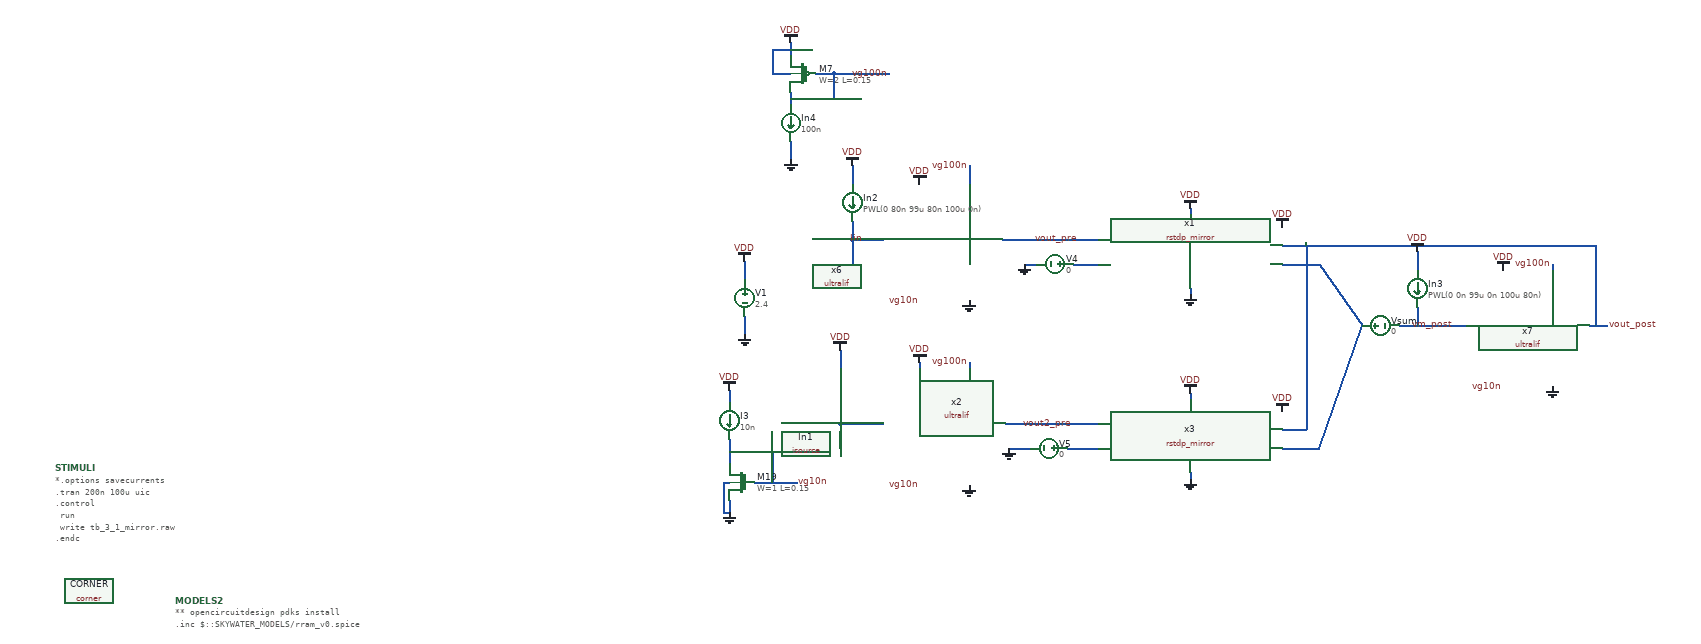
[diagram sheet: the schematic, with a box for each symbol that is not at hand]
v {xschem version=3.4.5 file_version=1.2
}
G {}
K {}
V {}
S {}
E {}
B 2 1390 -105 2190 295 {flags=graph
y1=1.8
y2=5.3
ypos1=0
ypos2=2
divy=5
subdivy=1
unity=1
x1=2e-09
x2=0.0001
divx=5
subdivx=1
xlabmag=1.0
ylabmag=1.0
node="\\"Fil1; 5 n.x1.x1.xr2.n1#ngap -\\"

\\"Fil2; 5 n.x3.x1.xr2.n1#ngap - \\"

\\"Fil2; 5 n.x5.x1.xr2.n1#ngap - \\""
color="6 8 7"
dataset=-1
unitx=1
logx=0
logy=0
}
B 2 1355 535 2155 935 {flags=graph
y1=-1.4047916
y2=0.79520803
ypos1=0
ypos2=2
divy=5
subdivy=1
unity=1
x1=2e-09
x2=0.0001
divx=5
subdivx=1
xlabmag=1.0
ylabmag=1.0


dataset=-1
unitx=1
logx=0
logy=0
color=4
node="\\"Vmem1; x1.x1.BE x1.x1.TE - \\""}
B 2 1620 -610 2420 -210 {flags=graph
y1=-0.0056
y2=2.5
ypos1=0
ypos2=2
divy=5
subdivy=1
unity=1
x1=2e-09
x2=0.0001
divx=5
subdivx=1
xlabmag=1.0
ylabmag=1.0


dataset=-1
unitx=1
logx=0
logy=0
color=8
node=vout_post}
B 2 -1232.5 -695 -432.5 -295 {flags=graph
y1=-0.00026
y2=2.5
ypos1=0
ypos2=2
divy=5
subdivy=1
unity=1
x1=2e-09
x2=0.0001
divx=5
subdivx=1
xlabmag=1.0
ylabmag=1.0


dataset=-1
unitx=1
logx=0
logy=0
color=6
node=vout_pre}
B 2 -200 -740 600 -340 {flags=graph
y1=-2.4011863e-07
y2=1.3746887e-06
ypos1=0
ypos2=2
divy=5
subdivy=1
unity=1
x1=2e-09
x2=0.0001
divx=5
subdivx=1
xlabmag=1.0
ylabmag=1.0


dataset=-1
unitx=1
logx=0
logy=0
color=6
node=i(Vsum)}
B 2 -1225 -177.5 -425 222.5 {flags=graph
y1=-0.0017
y2=2.8
ypos1=0
ypos2=2
divy=5
subdivy=1
unity=1
x1=2e-09
x2=0.0001
divx=5
subdivx=1
xlabmag=1.0
ylabmag=1.0


dataset=-1
unitx=1
logx=0
logy=0
color=8
node=vout2_pre}
B 2 702.5 -630 1502.5 -230 {flags=graph
y1=0.018
y2=1.7
ypos1=0
ypos2=2
divy=5
subdivy=1
unity=1
x1=2e-09
x2=0.0001
divx=5
subdivx=1
xlabmag=1.0
ylabmag=1.0


dataset=-1
unitx=1
logx=0
logy=0




color=4
node=x7.vm}
B 2 402.5 515 1202.5 915 {flags=graph
y1=-0.0011
y2=1.3
ypos1=0
ypos2=2
divy=5
subdivy=1
unity=1
x1=2e-09
x2=0.0001
divx=5
subdivx=1
xlabmag=1.0
ylabmag=1.0


dataset=-1
unitx=1
logx=0
logy=0




color=4
node=x7.vg}
B 2 -557.5 530 242.5 930 {flags=graph
y1=-1.4e-06
y2=3.9e-06
ypos1=0
ypos2=2
divy=5
subdivy=1
unity=1
x1=2e-09
x2=0.0001
divx=5
subdivx=1
xlabmag=1.0
ylabmag=1.0


dataset=-1
unitx=1
logx=0
logy=0




color=4
node=i(v4)}
N -175 125 -175 155 {
lab=GND}
N -175 35 -175 65 {
lab=VDD}
N -200 325 -200 365 {
lab=vg10n}
N -200 245 -200 265 {
lab=VDD}
N -200 425 -200 445 {
lab=GND}
N -210 395 -200 395 {
lab=GND}
N -210 395 -210 445 {
lab=GND}
N -210 445 -200 445 {
lab=GND}
N -160 395 -90 395 {
lab=vg10n}
N -200 345 -130 345 {
lab=vg10n}
N -130 345 -130 395 {
lab=vg10n}
N 550 -50 550 -40 {
lab=VDD}
N 340 0 400 0 {
lab=vout_pre}
N 550 80 550 90 {
lab=GND}
N 0 0 50 0 {
lab=Iin}
N 0 -30 0 0 {
lab=Iin}
N 0 -120 0 -90 {
lab=VDD}
N -20 270 -20 300 {
lab=#net1}
N -20 180 -20 210 {
lab=VDD}
N -20 300 50 300 {
lab=#net1}
N 110 200 110 210 {
lab=VDD}
N 550 250 550 260 {
lab=VDD}
N 550 380 550 390 {
lab=GND}
N 340 300 400 300 {
lab=vout2_pre}
N 1200 140 1230 140 {
lab=vout_post}
N 930 10 1210 10 {
lab=vout_post}
N 1210 10 1210 140 {
lab=vout_post}
N -100 -320 -100 -300 {
lab=VDD}
N -130 -270 -100 -270 {
lab=VDD}
N -130 -310 -130 -270 {
lab=VDD}
N -130 -310 -100 -310 {
lab=VDD}
N -60 -270 -30 -270 {
lab=vg100n}
N -100 -240 -100 -220 {
lab=vg100n}
N -100 -160 -100 -130 {
lab=GND}
N -100 -230 -30 -230 {
lab=vg100n}
N -30 -270 -30 -230 {
lab=vg100n}
N -30 -270 60 -270 {
lab=vg100n}
N 190 -120 190 -90 {
lab=vg100n}
N 190 200 190 210 {
lab=vg100n}
N 1140 40 1140 50 {
lab=vg100n}
N 700 10 820 10 {
lab=vout_post}
N 820 10 930 10 {
lab=vout_post}
N 700 40 760 40 {
lab=#net2}
N 700 340 760 340 {
lab=#net2}
N 360 40 400 40 {
lab=#net3}
N 350 340 400 340 {
lab=#net4}
N 890 140 1000 140 {
lab=vm_post}
N 920 20 920 50 {
lab=VDD}
N 920 110 920 140 {
lab=vm_post}
N 760 340 830 140 {
lab=#net2}
N 760 40 830 140 {
lab=#net2}
N 245 -0 340 0 {
lab=vout_pre}
N -0 -0 0 40 {
lab=Iin}
N -20 300 -20 340 {
lab=#net1}
N 250 300 340 300 {
lab=vout2_pre}
N 255 340 290 340 {
lab=GND}
N 280 40 300 40 {
lab=GND}
N 740 10 740 305 {
lab=vout_post}
N 700 310 740 310 {
lab=vout_post}
N 740 305 740 310 {
lab=vout_post}
C {devices/vsource.sym} -175 95 0 0 {name=V1 value=2.4 savecurrent=false}
C {devices/vdd.sym} -175 35 0 0 {name=l1 lab=VDD}
C {devices/gnd.sym} -175 155 0 0 {name=l2 lab=GND}
C {sky130_fd_pr/corner.sym} -1242.5 572.5 0 0 {name=CORNER only_toplevel=true corner=tt}
C {devices/code_shown.sym} -1297.5 372.5 0 0 {name=STIMULI 
only_toplevel=true
place=end
value="
*.options savecurrents
.tran 200n 100u uic
.control
	run
	write tb_3_1_mirror.raw
.endc
"}
C {devices/code.sym} -1102.5 587.5 0 0 {name=MODELS2
only_toplevel=true
format="tcleval( @value )"
value="
** opencircuitdesign pdks install
.inc $::SKYWATER_MODELS/rram_v0.spice
"
spice_ignore=false}
C {/home/alex/Desktop/EDA/SNN_IPN/Neuron/ultralif/ultralif.sym} 150 0 0 0 {name=x6}
C {/home/alex/Desktop/EDA/SNN_IPN/Neuron/ultralif/ultralif.sym} 1100 140 0 0 {name=x7}
C {sky130_fd_pr/nfet_01v8.sym} -180 395 0 1 {name=M19
L=0.15
W=1
nf=1 
mult=1
ad="'int((nf+1)/2) * W/nf * 0.29'" 
pd="'2*int((nf+1)/2) * (W/nf + 0.29)'"
as="'int((nf+2)/2) * W/nf * 0.29'" 
ps="'2*int((nf+2)/2) * (W/nf + 0.29)'"
nrd="'0.29 / W'" nrs="'0.29 / W'"
sa=0 sb=0 sd=0
model=nfet_01v8
spiceprefix=X
}
C {devices/isource.sym} -200 295 0 0 {name=I3 value=10n}
C {devices/vdd.sym} -200 245 0 0 {name=l30 lab=VDD}
C {devices/gnd.sym} -200 445 0 0 {name=l31 lab=GND}
C {devices/vdd.sym} 110 -90 0 0 {name=l3 lab=VDD}
C {devices/gnd.sym} 190 100 0 0 {name=l4 lab=GND}
C {devices/gnd.sym} 1140 240 0 0 {name=l5 lab=GND}
C {devices/vdd.sym} 1060 50 0 0 {name=l6 lab=VDD}
C {devices/vdd.sym} 550 -50 0 0 {name=l10 lab=VDD}
C {devices/gnd.sym} 550 90 0 0 {name=l11 lab=GND}
C {devices/lab_pin.sym} 20 0 3 0 {name=p2 sig_type=std_logic lab=Iin}
C {devices/vdd.sym} 0 -120 0 0 {name=l52 lab=VDD}
C {devices/lab_pin.sym} 370 0 1 0 {name=p1 sig_type=std_logic lab=vout_pre}
C {devices/lab_pin.sym} 1230 140 0 1 {name=p3 sig_type=std_logic lab=vout_post}
C {devices/launcher.sym} -1187.5 802.5 0 0 {name=h5
descr="load waves" 
tclcommand="xschem raw_read $netlist_dir/tb_3_1_mirror.raw tran"
}
C {/home/alex/Desktop/EDA/SNN_IPN/Neuron/ultralif/ultralif.sym} 150 300 0 0 {name=x2}
C {devices/gnd.sym} 190 400 0 0 {name=l7 lab=GND}
C {devices/vdd.sym} -20 180 0 0 {name=l12 lab=VDD}
C {devices/vdd.sym} 110 200 0 0 {name=l13 lab=VDD}
C {devices/vdd.sym} 550 250 0 0 {name=l14 lab=VDD}
C {devices/gnd.sym} 550 390 0 0 {name=l15 lab=GND}
C {devices/lab_pin.sym} 360 300 1 0 {name=p5 sig_type=std_logic lab=vout2_pre}
C {devices/vdd.sym} 700 -20 0 0 {name=l9 lab=VDD}
C {sky130_fd_pr/pfet_01v8.sym} -80 -270 0 1 {name=M7
L=0.15
W=2
nf=1
mult=1
ad="'int((nf+1)/2) * W/nf * 0.29'" 
pd="'2*int((nf+1)/2) * (W/nf + 0.29)'"
as="'int((nf+2)/2) * W/nf * 0.29'" 
ps="'2*int((nf+2)/2) * (W/nf + 0.29)'"
nrd="'0.29 / W'" nrs="'0.29 / W'"
sa=0 sb=0 sd=0
model=pfet_01v8
spiceprefix=X
}
C {devices/vdd.sym} -100 -320 0 0 {name=l8 lab=VDD}
C {devices/isource.sym} -100 -190 0 1 {name=In4 value=100n }
C {devices/gnd.sym} -100 -130 0 0 {name=l17 lab=GND}
C {devices/lab_pin.sym} 60 -270 3 0 {name=p7 sig_type=std_logic lab=vg100n}
C {devices/lab_pin.sym} 190 -120 1 0 {name=p8 sig_type=std_logic lab=vg100n}
C {devices/lab_pin.sym} 190 200 1 0 {name=p9 sig_type=std_logic lab=vg100n}
C {devices/lab_pin.sym} 1140 40 1 0 {name=p11 sig_type=std_logic lab=vg100n}
C {/home/alex/Desktop/EDA/SNN_IPN/Synapse/rstdp_mirror.sym} 550 0 0 0 {name=x1}
C {/home/alex/Desktop/EDA/SNN_IPN/Synapse/rstdp_mirror.sym} 550 300 0 0 {name=x3}
C {devices/vsource.sym} 330 40 1 0 {name=V4 value=0 }
C {devices/vsource.sym} 320 340 1 0 {name=V5 value=0 }
C {devices/isource.sym} 0 -60 0 1 {name=In2 value="PWL(0 80n 99u 80n 100u 0n)"
spice_ignore=false}
C {devices/vsource.sym} 860 140 3 0 {name=Vsum value=0 }
C {devices/lab_pin.sym} 980 140 1 0 {name=p4 sig_type=std_logic lab=vm_post}
C {devices/vdd.sym} 920 20 0 0 {name=l16 lab=VDD}
C {devices/isource.sym} -20 245 0 1 {name=In1 value="PWL(0 60n 99u 60n 100u 0n)"
spice_ignore=false}
C {devices/isource.sym} 920 80 0 1 {name=In3 value="PWL(0 0n 99u 0n 100u 80n)"
spice_ignore=false}
C {devices/lab_pin.sym} -90 395 2 0 {name=p6 sig_type=std_logic lab=vg10n}
C {devices/lab_pin.sym} 110 400 3 0 {name=p10 sig_type=std_logic lab=vg10n}
C {devices/lab_pin.sym} 110 100 3 0 {name=p12 sig_type=std_logic lab=vg10n}
C {devices/lab_pin.sym} 1060 240 3 0 {name=p13 sig_type=std_logic lab=vg10n}
C {devices/vdd.sym} 700 280 0 0 {name=l20 lab=VDD}
C {devices/gnd.sym} 255 340 0 0 {name=l19 lab=GND}
C {devices/gnd.sym} 280 40 0 0 {name=l18 lab=GND}
